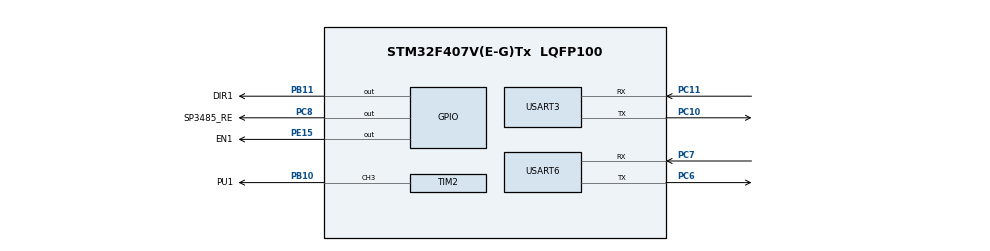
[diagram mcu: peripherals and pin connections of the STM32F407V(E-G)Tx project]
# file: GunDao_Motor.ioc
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Dma.Request0=USART3_RX
Dma.Request1=USART3_TX
Dma.USART3_RX.0.Direction=DMA_PERIPH_TO_MEMORY
Dma.USART3_RX.0.FIFOMode=DMA_FIFOMODE_DISABLE
Dma.USART3_RX.0.Instance=DMA1_Stream1
Dma.USART3_RX.0.MemDataAlignment=DMA_MDATAALIGN_BYTE
Dma.USART3_RX.0.MemInc=DMA_MINC_ENABLE
Dma.USART3_RX.0.Mode=DMA_NORMAL
Dma.USART3_RX.0.PeriphDataAlignment=DMA_PDATAALIGN_BYTE
Dma.USART3_RX.0.PeriphInc=DMA_PINC_DISABLE
Dma.USART3_RX.0.Priority=DMA_PRIORITY_LOW
Dma.USART3_TX.1.Direction=DMA_MEMORY_TO_PERIPH
Dma.USART3_TX.1.FIFOMode=DMA_FIFOMODE_DISABLE
Dma.USART3_TX.1.Instance=DMA1_Stream3
Dma.USART3_TX.1.MemDataAlignment=DMA_MDATAALIGN_BYTE
Dma.USART3_TX.1.MemInc=DMA_MINC_ENABLE
Dma.USART3_TX.1.Mode=DMA_NORMAL
Dma.USART3_TX.1.PeriphDataAlignment=DMA_PDATAALIGN_BYTE
Dma.USART3_TX.1.PeriphInc=DMA_PINC_DISABLE
Dma.USART3_TX.1.Priority=DMA_PRIORITY_LOW
Mcu.Family=STM32F4
Mcu.Name=STM32F407V(E-G)Tx
Mcu.Package=LQFP100
NVIC.DMA1_Stream1_IRQn=true\:0\:0\:false\:false\:true\:false\:true\:true
NVIC.DMA1_Stream3_IRQn=true\:0\:0\:false\:false\:true\:false\:true\:true
NVIC.PriorityGroup=NVIC_PRIORITYGROUP_4
NVIC.TIM2_IRQn=true\:0\:0\:false\:false\:true\:true\:true\:true
NVIC.USART3_IRQn=true\:0\:0\:false\:false\:true\:false\:true\:true
PA13.Mode=Serial_Wire
PA13.Signal=SYS_JTMS-SWDIO
PA14.Mode=Serial_Wire
PA14.Signal=SYS_JTCK-SWCLK
PB10.GPIO_Label=PU1
PB10.Signal=S_TIM2_CH3
PB11.GPIO_Label=DIR1
PB11.Signal=GPIO_Output
PC10.Mode=Asynchronous
PC10.Signal=USART3_TX
PC11.Mode=Asynchronous
PC11.Signal=USART3_RX
PC6.Mode=Asynchronous
PC6.Signal=USART6_TX
PC7.Mode=Asynchronous
PC7.Signal=USART6_RX
PC8.GPIO_Label=SP3485_RE
PC8.Signal=GPIO_Output
PE15.GPIO_Label=EN1
PE15.Signal=GPIO_Output
PH0-OSC_IN.Mode=HSE-External-Oscillator
PH0-OSC_IN.Signal=RCC_OSC_IN
PH1-OSC_OUT.Mode=HSE-External-Oscillator
PH1-OSC_OUT.Signal=RCC_OSC_OUT
ProjectManager.HeapSize=0x200
ProjectManager.StackSize=0x400
ProjectManager.TargetToolchain=CMake
RCC.48MHZClocksFreq_Value=84000000
RCC.AHBFreq_Value=168000000
RCC.APB1CLKDivider=RCC_HCLK_DIV4
RCC.APB1Freq_Value=42000000
RCC.APB1TimFreq_Value=84000000
RCC.APB2CLKDivider=RCC_HCLK_DIV2
RCC.APB2Freq_Value=84000000
RCC.APB2TimFreq_Value=168000000
RCC.CortexFreq_Value=168000000
RCC.HCLKFreq_Value=168000000
RCC.HSE_VALUE=8000000
RCC.HSI_VALUE=16000000
RCC.LSE_VALUE=32768
RCC.PLLM=4
RCC.PLLN=168
RCC.PLLSourceVirtual=RCC_PLLSOURCE_HSE
RCC.SYSCLKFreq_VALUE=168000000
RCC.SYSCLKSource=RCC_SYSCLKSOURCE_PLLCLK
RCC.VCOOutputFreq_Value=336000000
SH.S_TIM2_CH3.0=TIM2_CH3,PWM Generation3 CH3
TIM2.AutoReloadPreload=TIM_AUTORELOAD_PRELOAD_ENABLE
TIM2.Channel-PWM\ Generation3\ CH3=TIM_CHANNEL_3
TIM2.Period=3999
TIM2.Prescaler=2
TIM2.Pulse-PWM\ Generation3\ CH3=2000
USART3.VirtualMode=VM_ASYNC
USART6.VirtualMode=VM_ASYNC
VP_TIM2_VS_ClockSourceINT.Mode=Internal
board=custom

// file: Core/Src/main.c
/* USER CODE BEGIN Header */
/**
  ******************************************************************************
  * @file           : main.c
  * @brief          : Main program body
  ******************************************************************************
  * @attention
  *
  * Copyright (c) 2025 STMicroelectronics.
  * All rights reserved.
  *
  * This software is licensed under terms that can be found in the LICENSE file
  * in the root directory of this software component.
  * If no LICENSE file comes with this software, it is provided AS-IS.
  *
  ******************************************************************************
  */
/* USER CODE END Header */
#include <math.h>
#include <string.h>
#include "main.h"
#include "dma.h"
#include "tim.h"
#include "usart.h"
#include "gpio.h"

/* USER CODE BEGIN PM */
#pragma pack(1)
typedef union {
    //缓冲区指针
    uint8_t ptr[9];
    //数据结构体
    struct {
        //帧头
        uint16_t head;
        //功能码
        uint8_t fun;
        //数据
        union {
            uint8_t arr[4];
            float f32;
            uint32_t u32;
        } data;
        //帧尾
        uint16_t end;
    } B;
} Pkg;
#pragma pack()
Pkg buffer;
Pkg tx_buffer;

/* USER CODE END PM */

/* USER CODE BEGIN PV */
uint32_t singleStepPulse = 40;
uint32_t circlePulse = 15000;
int32_t currentAngle_pulse = 0;
int32_t dir_flag = 0;
uint32_t tmpPulse = 0;
uint8_t isSingleMod = 0;
uint8_t isWorking = 0;//是否正在采集
uint32_t checkTmp = 0;//采集角度的中间变量
uint32_t checkCount = 0;
/* USER CODE END PV */

void SystemClock_Config(void);

/* USER CODE BEGIN 0 */

float getCurrentAngle_f32() {
    return (float) currentAngle_pulse * 360.0f / (float) circlePulse;
}

void motor_start_work() {
    HAL_UART_Transmit(&huart3, buffer.ptr, 9, 0xffff);
    memcpy(tx_buffer.ptr, buffer.ptr, 9);
    checkTmp = 0;
    isWorking = 1;
    dir_flag = 1;
    HAL_GPIO_WritePin(DIR1_GPIO_Port, DIR1_Pin, GPIO_PIN_SET);
    HAL_TIM_PWM_Start(&htim2, TIM_CHANNEL_3);
}

void motor_stop_work() {
    checkCount = 0;
    tx_buffer.B.fun = 0X09;
    tx_buffer.B.data.f32 = getCurrentAngle_f32();
    HAL_UART_Transmit_DMA(&huart3, tx_buffer.ptr, 9);
    HAL_TIM_PWM_Stop(&htim2, TIM_CHANNEL_3);
    isWorking = 0;
    checkTmp = 0;
}

void HAL_TIM_PeriodElapsedCallback(TIM_HandleTypeDef *htim) {
    if (htim->Instance == TIM2) {
        if (dir_flag) {
            currentAngle_pulse++;
        } else {
            currentAngle_pulse--;
        }
        if (currentAngle_pulse > (int32_t) circlePulse) {
            currentAngle_pulse = 0;
        } else if (currentAngle_pulse < 0) {
            currentAngle_pulse = (int32_t) circlePulse;
        }
        if (isWorking) {
            checkTmp++;
            checkCount++;

            if (checkCount >= circlePulse) {
                motor_stop_work();
            } else if (checkTmp >= singleStepPulse) {
                checkTmp = 0;
                tx_buffer.B.data.f32 = getCurrentAngle_f32();
                HAL_UART_Transmit_DMA(&huart3, tx_buffer.ptr, 9);
            }
        }
    }
}

void motor_start_u() {
    dir_flag = 1;
    HAL_GPIO_WritePin(DIR1_GPIO_Port, DIR1_Pin, GPIO_PIN_SET);
    HAL_TIM_PWM_Start(&htim2, TIM_CHANNEL_3);
    HAL_UART_Transmit(&huart3, buffer.ptr, 9, 0xffff);
}

void motor_start_d() {
    dir_flag = 0;
    HAL_GPIO_WritePin(DIR1_GPIO_Port, DIR1_Pin, GPIO_PIN_RESET);
    HAL_TIM_PWM_Start(&htim2, TIM_CHANNEL_3);
    HAL_UART_Transmit(&huart3, buffer.ptr, 9, 0xffff);
}

void motor_stop() {
    isWorking = 0;
    dir_flag = 0;
    HAL_TIM_PWM_Stop(&htim2, TIM_CHANNEL_3);
    HAL_UART_Transmit(&huart3, buffer.ptr, 9, 0xffff);
}

void setSpeedPulse(uint32_t pulse_s) {
    uint32_t arr = (84000000 / (htim2.Init.Prescaler + 1)) / pulse_s;
    TIM2->ARR = arr - 1;
    TIM2->CCR3 = (arr / 2) - 1;

}

/**
 * @defgroup head
 * 帧头       0xEF 0xFE
 * 指令码     0x00:设置单步脉冲个数 uint_32
 *           0x01:一圈脉冲个数设置 uint_32
 *           0x02:最高转速设置    uint_32
 *           0x03:零点位置设置    none
 *           0x04:获取当前角度
 *           0x05:开始采集
 *           0x06:正向转动
 *           0x07:反向转动
 *           0x08:停止
 *           0x0A:通知需要请求数据
 *           0x0B:Busy
 * 数据       32位
 * 帧尾
 * @param huart
 * @param Size
 */
void HAL_UARTEx_RxEventCallback(UART_HandleTypeDef *huart, uint16_t Size) {
    if (huart->Instance == USART3) {
        if (Size >= 9) {
            if (buffer.B.head == 0xFEEF && buffer.B.end == 0xEEFF) {
                switch (buffer.B.fun) {
                    //设置每隔多少脉冲发送一次处理数据指令
                    case 0: {
                        singleStepPulse = buffer.B.data.u32;
                        HAL_UART_Transmit(&huart3, buffer.ptr, 9, 0xffff);
                        break;
                    }
                        //设置转一圈需要多少脉冲
                    case 1: {
                        circlePulse = buffer.B.data.u32;
                        HAL_UART_Transmit(&huart3, buffer.ptr, 9, 0xffff);
                        break;
                    }
                        //最高转速设置
                    case 2: {
                        setSpeedPulse(buffer.B.data.u32);
                        HAL_UART_Transmit(&huart3, buffer.ptr, 9, 0xffff);
                        break;
                    }
                        //当前角度清0
                    case 3: {
                        currentAngle_pulse = 0;
                        buffer.B.data.u32 = currentAngle_pulse;
                        HAL_UART_Transmit(&huart3, buffer.ptr, 9, 0xffff);
                        break;
                    }
                        //获取当前角度
                    case 4: {
                        buffer.B.data.f32 = getCurrentAngle_f32();
                        HAL_UART_Transmit(&huart3, buffer.ptr, 9, 0xffff);
                        break;
                    }

                    case 5: {
                        motor_start_work();
                        break;
                    }
                    case 6: {
                        motor_start_u();
                        break;
                    }
                    case 7: {
                        motor_start_d();
                        break;
                    }
                    case 8: {
                        motor_stop();
                        break;
                    }
                    case 9: {
                        motor_stop_work();

                        break;
                    }
                    default:
                        break;
                }
            }
        }

        HAL_UARTEx_ReceiveToIdle_DMA(&huart3, buffer.ptr, 9);
    }
}
/* USER CODE END 0 */

int main(void) {

    /* MCU Configuration--------------------------------------------------------*/

    /* Reset of all peripherals, Initializes the Flash interface and the Systick. */
    HAL_Init();

    /* Configure the system clock */
    SystemClock_Config();

    /* Initialize all configured peripherals */
    MX_GPIO_Init();
    MX_DMA_Init();
    MX_TIM2_Init();
    MX_USART3_UART_Init();
    MX_USART6_UART_Init();
    /* USER CODE BEGIN 2 */
    HAL_TIM_Base_Start_IT(&htim2);
    HAL_TIM_PWM_Stop(&htim2, TIM_CHANNEL_3);
    HAL_UARTEx_ReceiveToIdle_DMA(&huart3, buffer.ptr, 9);
    setSpeedPulse(125);
    /* USER CODE END 2 */

    /* Infinite loop */
    while (1) {

        /* USER CODE BEGIN 3 */
    }
}

/**
  * @brief System Clock Configuration
  * @retval None
  */
void SystemClock_Config(void) {
    RCC_OscInitTypeDef RCC_OscInitStruct = {0};
    RCC_ClkInitTypeDef RCC_ClkInitStruct = {0};

    /** Configure the main internal regulator output voltage
    */
    __HAL_RCC_PWR_CLK_ENABLE();
    __HAL_PWR_VOLTAGESCALING_CONFIG(PWR_REGULATOR_VOLTAGE_SCALE1);
    RCC_ClkInitStruct.ClockType = RCC_CLOCKTYPE_SYSCLK;
    RCC_ClkInitStruct.SYSCLKSource = RCC_SYSCLKSOURCE_HSI;

    if (HAL_RCC_ClockConfig(&RCC_ClkInitStruct, FLASH_LATENCY_5) != HAL_OK) {
        Error_Handler();
    }
    /** Initializes the RCC Oscillators according to the specified parameters
    * in the RCC_OscInitTypeDef structure.
    */
    RCC_OscInitStruct.OscillatorType = RCC_OSCILLATORTYPE_HSE;
    RCC_OscInitStruct.HSEState = RCC_HSE_ON;
    RCC_OscInitStruct.PLL.PLLState = RCC_PLL_ON;
    RCC_OscInitStruct.PLL.PLLSource = RCC_PLLSOURCE_HSE;
    RCC_OscInitStruct.PLL.PLLM = 4;
    RCC_OscInitStruct.PLL.PLLN = 168;
    RCC_OscInitStruct.PLL.PLLP = RCC_PLLP_DIV2;
    RCC_OscInitStruct.PLL.PLLQ = 4;
    if (HAL_RCC_OscConfig(&RCC_OscInitStruct) != HAL_OK) {
        Error_Handler();
    }

    /** Initializes the CPU, AHB and APB buses clocks
    */
    RCC_ClkInitStruct.ClockType = RCC_CLOCKTYPE_HCLK | RCC_CLOCKTYPE_SYSCLK
                                  | RCC_CLOCKTYPE_PCLK1 | RCC_CLOCKTYPE_PCLK2;
    RCC_ClkInitStruct.SYSCLKSource = RCC_SYSCLKSOURCE_PLLCLK;
    RCC_ClkInitStruct.AHBCLKDivider = RCC_SYSCLK_DIV1;
    RCC_ClkInitStruct.APB1CLKDivider = RCC_HCLK_DIV4;
    RCC_ClkInitStruct.APB2CLKDivider = RCC_HCLK_DIV2;

    if (HAL_RCC_ClockConfig(&RCC_ClkInitStruct, FLASH_LATENCY_5) != HAL_OK) {
        Error_Handler();
    }
}

#if 0
/* USER CODE END 3 */
}

void SystemClock_Config(void)
{
RCC_OscInitTypeDef RCC_OscInitStruct = {0};
RCC_ClkInitTypeDef RCC_ClkInitStruct = {0};

/** Configure the main internal regulator output voltage
*/
__HAL_RCC_PWR_CLK_ENABLE();
__HAL_PWR_VOLTAGESCALING_CONFIG(PWR_REGULATOR_VOLTAGE_SCALE1);

/** Initializes the RCC Oscillators according to the specified parameters
* in the RCC_OscInitTypeDef structure.
*/
RCC_OscInitStruct.OscillatorType = RCC_OSCILLATORTYPE_HSE;
RCC_OscInitStruct.HSEState = RCC_HSE_ON;
RCC_OscInitStruct.PLL.PLLState = RCC_PLL_ON;
RCC_OscInitStruct.PLL.PLLSource = RCC_PLLSOURCE_HSE;
RCC_OscInitStruct.PLL.PLLM = 4;
RCC_OscInitStruct.PLL.PLLN = 168;
RCC_OscInitStruct.PLL.PLLP = RCC_PLLP_DIV2;
RCC_OscInitStruct.PLL.PLLQ = 4;
if (HAL_RCC_OscConfig(&RCC_OscInitStruct) != HAL_OK)
{
  Error_Handler();
}

/** Initializes the CPU, AHB and APB buses clocks
*/
RCC_ClkInitStruct.ClockType = RCC_CLOCKTYPE_HCLK|RCC_CLOCKTYPE_SYSCLK
                            |RCC_CLOCKTYPE_PCLK1|RCC_CLOCKTYPE_PCLK2;
RCC_ClkInitStruct.SYSCLKSource = RCC_SYSCLKSOURCE_PLLCLK;
RCC_ClkInitStruct.AHBCLKDivider = RCC_SYSCLK_DIV1;
RCC_ClkInitStruct.APB1CLKDivider = RCC_HCLK_DIV4;
RCC_ClkInitStruct.APB2CLKDivider = RCC_HCLK_DIV2;

if (HAL_RCC_ClockConfig(&RCC_ClkInitStruct, FLASH_LATENCY_5) != HAL_OK)
{
  Error_Handler();
}
}

/* USER CODE BEGIN 4 */
#endif
/* USER CODE END 4 */

void Error_Handler(void) {
    __disable_irq();
    while (1) {
    }
}
